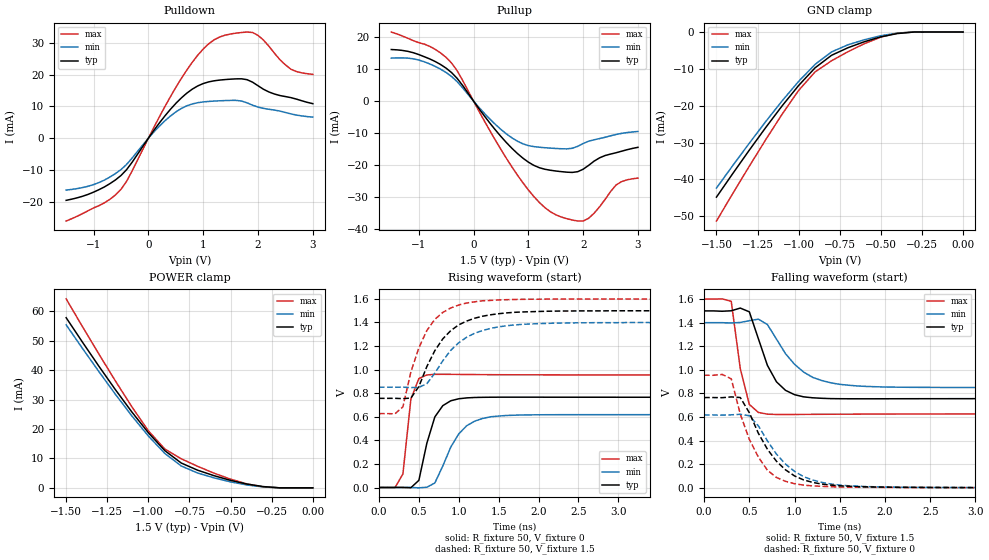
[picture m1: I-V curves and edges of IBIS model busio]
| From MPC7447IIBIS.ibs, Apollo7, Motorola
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| *   busio Model   *
[Model]   busio
Model_type   I/O
Polarity   Non-Inverting
Vinl = 0.53V
Vinh = 0.98V
Vmeas = 0.75V
Cref = 0
Rref = 50
Vref = 0.75V
|   typ   min   max
C_comp   4.564427e-12   3.697268e-12   4.652796e-12
|   typ   min   max
[Voltage range]   1.5V   1.4V   1.6V
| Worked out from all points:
|   slope of the pulldown table from 0 to 0.225 V, typ, clamps not added: 42.3 ohm
|   slope of the pullup table from 0 to 0.225 V, typ, clamps not added: 42.8 ohm
|   GND clamp passes 1 mA (typ) near -0.47 V on its own axis
|   POWER clamp passes 1 mA (typ) near -0.37 V on its own axis
|   falling waveform, R_fixture 50, V_fixture 1.5: 20-80 % time 234ps typ, 371ps min, 131ps max; typ from 1.5 V to 0.756 V
|   rising waveform, R_fixture 50, V_fixture 0: 20-80 % time 185ps typ, 297ps min, 95.8ps max; typ from 0 V to 0.766 V
|   falling waveform, R_fixture 50, V_fixture 0: 20-80 % time 385ps typ, 411ps min, 309ps max; typ from 0.766 V to 0 V
|   rising waveform, R_fixture 50, V_fixture 1.5: 20-80 % time 413ps typ, 455ps min, 332ps max; typ from 0.756 V to 1.5 V
[Pulldown]
|   Voltage   I(typ)   I(min)   I(max)
-1.5V     -19.49mA   -16.28mA   -25.98mA
-1V       -16.92mA   -14.55mA   -21.87mA
-500mV    -11.7mA    -9.847mA   -16.03mA
200mV     4.775mA    3.783mA    6.694mA
500mV     10.92mA    8.247mA    15.92mA
900mV     16.41mA    11.15mA    26.04mA
1.2V      18.03mA    11.67mA    30.89mA
1.6V      18.63mA    11.88mA    32.98mA
1.9V      17.6mA     10.38mA    33.18mA
2.2V      14.52mA    9.085mA    28.86mA
2.6V      12.75mA    7.64mA     21.66mA
3V        10.85mA    6.627mA    20.04mA
[GND_clamp]
-1.5V     -44.8mA    -42.34mA   -51.28mA
-1.3V     -32.04mA   -30.15mA   -36.39mA
-1.1V     -20mA      -18.65mA   -22.25mA
-1V       -14.49mA   -13.39mA   -15.83mA
-900mV    -9.704mA   -8.776mA   -10.81mA
-800mV    -6.312mA   -5.399mA   -7.799mA
-700mV    -4.256mA   -3.459mA   -5.335mA
-600mV    -2.625mA   -2.087mA   -3.148mA
-500mV    -1.298mA   -995.5uA   -1.373mA
-400mV    -412.1uA   -299.9uA   -290uA
-300mV    0A         0A         0A
0V        0A         0A         0A
[Pullup]
-1.5V     16.07mA    13.4mA     21.53mA
-1V       14.51mA    12.8mA     18.21mA
-700mV    12.33mA    10.81mA    16.13mA
-400mV    8.865mA    7.651mA    11.84mA
600mV     -12.96mA   -10.25mA   -17.88mA
1V        -19.05mA   -13.9mA    -27.72mA
1.4V      -21.59mA   -14.69mA   -34.5mA
1.8V      -22.27mA   -14.74mA   -37.11mA
2V        -21.27mA   -13.25mA   -37.43mA
2.2V      -18.75mA   -12.08mA   -35mA
2.6V      -16.13mA   -10.44mA   -26.2mA
3V        -14.44mA   -9.492mA   -24.04mA
[POWER_clamp]
-1.5V     57.83mA    55.41mA    64.24mA
-1.3V     41.26mA    39.44mA    45.38mA
-1.1V     25.75mA    24.43mA    27.52mA
-1V       18.72mA    17.62mA    19.38mA
-900mV    12.65mA    11.7mA     13.19mA
-800mV    8.431mA    7.427mA    9.883mA
-700mV    5.989mA    5.036mA    7.304mA
-500mV    2.538mA    2.024mA    2.95mA
-400mV    1.27mA     968.7uA    1.329mA
-300mV    421.8uA    300.9uA    317.7uA
-200mV    0A         0A         0A
0V        0A         0A         0A
|   typ   min   max
[Ramp]
dV/dt_r   0.45919/1.79025e-10   0.37058/2.85320e-10   0.57281/9.39856e-11
dV/dt_f   0.44622/2.26703e-10   0.32949/3.68104e-10   0.58381/1.07987e-10
[Falling Waveform]
R_fixture = 50
V_fixture = 1.5
V_fixture_min = 1.4
V_fixture_max = 1.6
| time   V(typ)   V(min)   V(max)
0s        1.5V       1.4V       1.6V
300ps     1.501V     1.398V     1.581V
400ps     1.524V     1.402V     1.01V
500ps     1.492V     1.417V     707mV
700ps     1.038V     1.384V     624.7mV
900ps     826.6mV    1.137V     621.7mV
1.1ns     771.6mV    981.9mV    622.7mV
1.4ns     756.5mV    891mV      624.1mV
1.8ns     755.1mV    859.7mV    625.2mV
19.7ns    756.3mV    850.8mV    627mV
[Rising Waveform]
R_fixture = 50
V_fixture = 0
V_fixture_min = 0
V_fixture_max = 0
| time   V(typ)   V(min)   V(max)
0s        223.5uV    243.3uV    162.4uV
200ps     1.005mV    -194.7uV   -1.617mV
300ps     150.1uV    1.597mV    114.7mV
400ps     -1.594mV   456.6uV    750.3mV
500ps     60.87mV    -2.859mV   924.3mV
700ps     598.6mV    38.14mV    959.8mV
900ps     735.7mV    343.2mV    959.8mV
1.1ns     760.1mV    524.2mV    958.5mV
1.6ns     766.2mV    611mV      956.4mV
19.7ns    765.5mV    617.9mV    954.8mV
[Falling Waveform]
R_fixture = 50
V_fixture = 0
V_fixture_min = 0
V_fixture_max = 0
| time   V(typ)   V(min)   V(max)
0s        765.5mV    617.9mV    954.8mV
300ps     770.9mV    618.9mV    924.4mV
400ps     765.8mV    623.7mV    625.3mV
500ps     636.9mV    611.6mV    411mV
700ps     327.2mV    398.7mV    149.5mV
900ps     152.8mV    201.2mV    55.15mV
1.2ns     46.26mV    67.1mV     16.67mV
1.6ns     13.61mV    17.77mV    5.971mV
2.5ns     3.591mV    3.927mV    2.389mV
19.7ns    230uV      252.5uV    168uV
[Rising Waveform]
R_fixture = 50
V_fixture = 1.5
V_fixture_min = 1.4
V_fixture_max = 1.6
| time   V(typ)   V(min)   V(max)
0s        756.3mV    850.8mV    627mV
200ps     756.5mV    850.4mV    624.7mV
300ps     753.8mV    851mV      684.4mV
400ps     758.6mV    847.4mV    980.7mV
500ps     856.1mV    849.1mV    1.185V
700ps     1.161V     969.8mV    1.426V
1ns       1.38V      1.228V     1.548V
1.3ns     1.453V     1.332V     1.584V
2.7ns     1.498V     1.398V     1.599V
19.7ns    1.5V       1.4V       1.6V
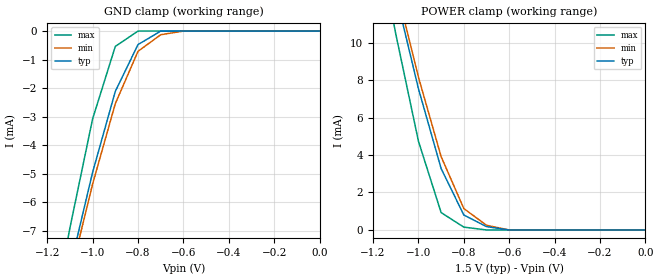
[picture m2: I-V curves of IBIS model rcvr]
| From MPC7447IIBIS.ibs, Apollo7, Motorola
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| *   rcvr  Model   *
[Model]   rcvr
Model_type   Input
Polarity   Non-Inverting
Vinl =   0.53V
Vinh =   0.98V
|   typ   min   max
C_comp   1.481368e-12   1.105652e-12   1.610064e-12
|   typ   min   max
[Voltage range]   1.5V   1.4V   1.6V
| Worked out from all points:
|   GND clamp passes 1 mA (typ) near -0.83 V on its own axis
|   POWER clamp passes 1 mA (typ) near -0.81 V on its own axis
|   Voltage(V)   I(typ)   I(min)   I(max)
[GND_clamp]
-1.5V     -23.28mA   -23.02mA   -24.65mA
-1.2V     -11.91mA   -12.08mA   -11.14mA
-1.1V     -8.313mA   -8.62mA    -6.904mA
-1V       -4.952mA   -5.364mA   -3.078mA
-900mV    -2.115mA   -2.545mA   -537.7uA
-800mV    -473.7uA   -709.1uA   0A
-700mV    0A         -127.9uA   0A
-600mV    0A         0A         0A
0V        0A         0A         0A
[POWER_clamp]
-1.5V     35.08mA    34.76mA    37.04mA
-1.2V     18mA       18.29mA    16.83mA
-1.1V     12.6mA     13.07mA    10.48mA
-1V       7.547mA    8.165mA    4.745mA
-900mV    3.279mA    3.916mA    927uA
-800mV    798.5uA    1.143mA    152.3uA
-700mV    178.6uA    251.1uA    0A
-600mV    0A         0A         0A
0V        0A         0A         0A
